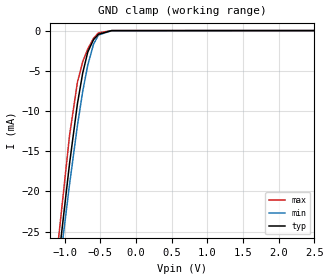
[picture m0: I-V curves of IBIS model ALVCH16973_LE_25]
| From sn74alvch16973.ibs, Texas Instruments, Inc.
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[Model]   ALVCH16973_LE_25
Model_type  Input
Vinl=0.7
Vinh=1.7
| variable   typ   min   max
C_comp   2.42pF   2.00pF   2.96pF
[Temperature Range]   40   100   -40
| Ambient temperature   25   85   -40
[Voltage range]   2.5   2.3   2.7
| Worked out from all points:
|   GND clamp passes 1 mA (typ) near -0.58 V on its own axis
[GND Clamp]
| ALVCH16973_LE_25
|   Voltage   I(typ)   I(min)   I(max)
-2.5V     -154.3mA   -145.9mA   -164.5mA
-1.145V   -33.47mA   -34.86mA   -31.33mA
-1.105V   -30.2mA    -31.85mA   -27.72mA
-1.085V   -28.58mA   -30.35mA   -25.93mA
-930mV    -16.54mA   -19.13mA   -13.04mA
-820mV    -9.124mA   -11.84mA   -6.44mA
-745mV    -5.25mA    -7.527mA   -3.847mA
-675mV    -2.681mA   -4.31mA    -2.304mA
-595mV    -1.134mA   -1.719mA   -967.5uA
-525mV    -460.2uA   -548.5uA   -284.1uA
-340mV    -6.934uA   -11.01uA   -976nA
2.5V      156.4pA    884.6pA    34.32pA
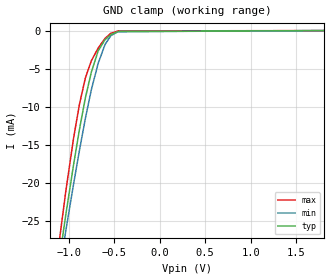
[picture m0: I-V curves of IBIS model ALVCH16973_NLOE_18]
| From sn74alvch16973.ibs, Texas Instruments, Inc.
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[Model]   ALVCH16973_NLOE_18
Model_type  Input
Vinl=0.5775
Vinh=1.2675
| variable   typ   min   max
C_comp   2.50pF   2.12pF   2.98pF
[Temperature Range]   40   100   -40
| Ambient temperature   25   85   -40
[Voltage range]   1.8   1.65   1.95
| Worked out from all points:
|   GND clamp passes 1 mA (typ) near -0.58 V on its own axis
[GND Clamp]
| ALVCH16973_NLOE_18
|   Voltage   I(typ)   I(min)   I(max)
-1.8V     -90.36mA   -87.06mA   -94.23mA
-1.34V    -49.88mA   -49.94mA   -49.51mA
-1.03V    -24.19mA   -26.29mA   -21.12mA
-945mV    -17.65mA   -20.18mA   -14.16mA
-880mV    -12.98mA   -15.72mA   -9.673mA
-815mV    -8.831mA   -11.53mA   -6.213mA
-750mV    -5.474mA   -7.789mA   -3.976mA
-675mV    -2.681mA   -4.31mA    -2.304mA
-600mV    -1.199mA   -1.844mA   -1.035mA
-535mV    -533.8uA   -655.1uA   -350.4uA
-455mV    -127.2uA   -144.7uA   -47.79uA
1.8V      127.8pA    817.9pA    24.46pA
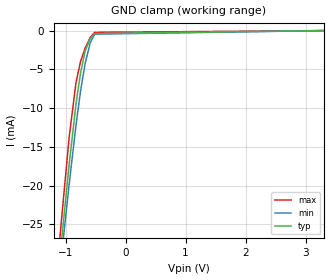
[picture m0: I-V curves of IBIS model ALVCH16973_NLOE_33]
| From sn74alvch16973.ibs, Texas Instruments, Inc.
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[Model]   ALVCH16973_NLOE_33
Model_type  Input
Vinl=0.8
Vinh=2.0
| variable   typ   min   max
C_comp   2.36pF   1.92pF   2.99pF
[Temperature Range]   40   100   -40
| Ambient temperature   25   85   -40
[Voltage range]   3.3   3   3.6
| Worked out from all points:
|   GND clamp passes 1 mA (typ) near -0.58 V on its own axis
[GND Clamp]
| ALVCH16973_NLOE_33
|   Voltage   I(typ)   I(min)   I(max)
-3.3V     -229.2mA   -214.9mA   -246.1mA
-1.15V    -33.88mA   -35.24mA   -31.79mA
-1.125V   -31.83mA   -33.35mA   -29.52mA
-1.1V     -29.79mA   -31.47mA   -27.27mA
-1.075V   -27.77mA   -29.61mA   -25.05mA
-940mV    -17.28mA   -19.83mA   -13.78mA
-825mV    -9.422mA   -12.15mA   -6.674mA
-750mV    -5.474mA   -7.789mA   -3.976mA
-675mV    -2.681mA   -4.31mA    -2.304mA
-590mV    -1.072mA   -1.6mA     -901.9uA
-515mV    -393.5uA   -457.8uA   -227.6uA
3.3V      193.8pA    964pA      46.32pA
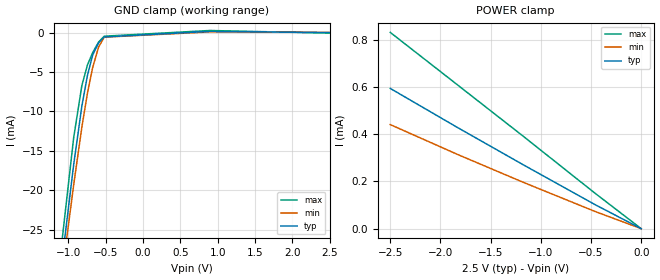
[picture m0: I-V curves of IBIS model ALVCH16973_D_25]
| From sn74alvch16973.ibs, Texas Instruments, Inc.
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[Model]   ALVCH16973_D_25
Model_type  Input
Vinl=0.7
Vinh=1.7
| variable   typ   min   max
C_comp   2.35pF   1.88pF   2.85pF
[Temperature Range]   40   100   -40
| Ambient temperature   25   85   -40
[Voltage range]   2.5   2.3   2.7
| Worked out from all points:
|   GND clamp passes 1 mA (typ) near -0.57 V on its own axis
[GND Clamp]
| ALVCH16973_D_25
|   Voltage   I(typ)   I(min)   I(max)
-2.5V     -155.1mA   -146.5mA   -165.4mA
-1.175V   -36.25mA   -37.4mA    -34.46mA
-1.13V    -32.52mA   -33.97mA   -30.34mA
-1.09V    -29.25mA   -30.96mA   -26.73mA
-930mV    -16.76mA   -19.32mA   -13.34mA
-820mV    -9.311mA   -11.99mA   -6.705mA
-745mV    -5.418mA   -7.653mA   -4.094mA
-675mV    -2.833mA   -4.418mA   -2.535mA
-595mV    -1.272mA   -1.81mA    -1.181mA
-520mV    -551.2uA   -580.9uA   -452.6uA
895mV     155.5uA    88.25uA    267.9uA
2.5V      166.5pA    30.52uA    -60.81uA
[POWER Clamp]
| ALVCH16973_D_25
|   Voltage   I(typ)   I(min)   I(max)
-2.5V     593.2uA    440.2uA    830.2uA
-1.825V   426.6uA    313.1uA    606.5uA
-1.175V   270.2uA    196uA      390.8uA
-460mV    101.7uA    72.75uA    149.9uA
-31.15fV  166.5pA    873.6pA    50.54pA
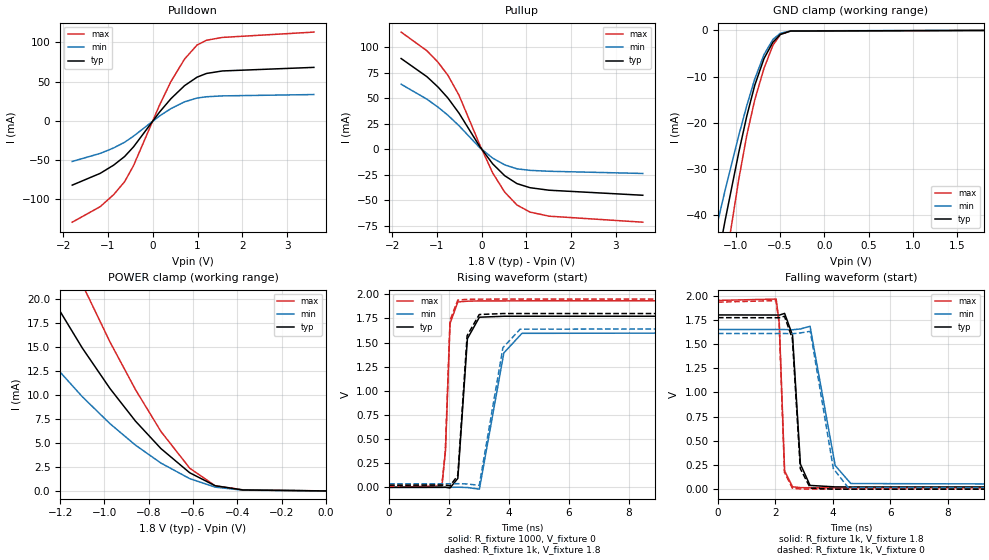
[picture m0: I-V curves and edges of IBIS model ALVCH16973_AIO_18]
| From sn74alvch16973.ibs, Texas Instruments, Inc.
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[Model]   ALVCH16973_AIO_18
Model_type  I/O
Vinl=0.5775
Vinh=1.2675
Enable   Active-Low
Vref =   0
Rref =   1000
Cref =   30p
Vmeas =   0.9
| variable   typ   min   max
C_comp   3.52pF   3.13pF   3.77pF
| C_pullup   4.75pF   3.65pF   5.30pF
| C_pulldown   5.07pF   3.29pF   6.70pF
| C_tri-state   3.52pF   3.13pF   3.77pF
[Temperature Range]   40   100   -40
| Ambient temperature   25   85   -40
[Voltage range]   1.8   1.65   1.95
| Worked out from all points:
|   slope of the pulldown table from 0 to 0.27 V, typ, clamps not added: 13.8 ohm
|   slope of the pullup table from 0 to 0.27 V, typ, clamps not added: 17.6 ohm
|   GND clamp passes 1 mA (typ) near -0.50 V on its own axis
|   POWER clamp passes 1 mA (typ) near -0.55 V on its own axis
|   rising waveform, R_fixture 1000, V_fixture 0: 20-80 % time 196ps typ, 355ps min, 120ps max; typ from 0 V to 1.77 V
|   falling waveform, R_fixture 1k, V_fixture 1.8: 20-80 % time 202ps typ, 380ps min, 121ps max; typ from 1.8 V to 0.023 V
|   rising waveform, R_fixture 1k, V_fixture 1.8: 20-80 % time 192ps typ, 335ps min, 119ps max; typ from 0.023 V to 1.8 V
|   falling waveform, R_fixture 1k, V_fixture 0: 20-80 % time 197ps typ, 366ps min, 120ps max; typ from 1.77 V to 0 V
[GND Clamp]
| ALVCH16973_AIO_18
|   Voltage   I(typ)   I(min)   I(max)
-1.8V     -114.4mA   -93.74mA   -142.9mA
-1.55V    -86.48mA   -71.1mA    -108.3mA
-1.325V   -62.23mA   -51.54mA   -77.86mA
-1.12V    -41.21mA   -34.65mA   -51.11mA
-965mV    -26.41mA   -22.72mA   -32.22mA
-875mV    -18.58mA   -16.31mA   -22.75mA
-785mV    -11.9mA    -10.53mA   -15.06mA
-680mV    -6.088mA   -5.234mA   -8.189mA
-580mV    -2.563mA   -1.963mA   -3.232mA
-495mV    -862.4uA   -609.1uA   -886.9uA
-380mV    -137.5uA   -100.9uA   -157.2uA
1.8V      633.6pA    17.14uA    -35.19uA
[POWER Clamp]
| ALVCH16973_AIO_18
|   Voltage   I(typ)   I(min)   I(max)
-1.8V     46.9mA     32mA       62.55mA
-1.505V   31.94mA    21.45mA    44.13mA
-1.37V    25.77mA    17.18mA    36.18mA
-1.235V   20.07mA    13.3mA     28.63mA
-1.1V     14.92mA    9.837mA    21.56mA
-975mV    10.69mA    7.019mA    15.55mA
-860mV    7.289mA    4.782mA    10.58mA
-745mV    4.421mA    2.907mA    6.209mA
-615mV    1.894mA    1.281mA    2.37mA
-500mV    537.7uA    395.3uA    541.3uA
-375mV    99.26uA    77.48uA    115.9uA
-16.28fV  633.6pA    1.888nA    58.65pA
[Pulldown]
| ALVCH16973_AIO_18
|   Voltage   I(typ)   I(min)   I(max)
-1.8V     -81.77mA   -51.62mA   -129mA
-1.175V   -66.78mA   -41.36mA   -109.2mA
-875mV    -56.33mA   -34.41mA   -93.93mA
-630mV    -45.37mA   -27.16mA   -77.47mA
-430mV    -33mA      -19.38mA   -56.92mA
150mV     11.21mA    6.297mA    20.03mA
405mV     28.31mA    15.69mA    50.14mA
710mV     44.96mA    24.35mA    78.83mA
990mV     55.79mA    29.2mA     96.74mA
1.2V      60.49mA    30.8mA     102.8mA
1.555V    63.68mA    31.91mA    106.4mA
3.6V      68.24mA    33.63mA    113.2mA
[Pullup]
| ALVCH16973_AIO_18
|   Voltage   I(typ)   I(min)   I(max)
-1.8V     89.09mA    63.89mA    115mA
-1.22V    71.17mA    49.14mA    96.57mA
-975mV    61.12mA    41.42mA    85.41mA
-755mV    50.4mA     33.55mA    72.69mA
-505mV    35.45mA    23.15mA    52.97mA
-50mV     3.259mA    2.011mA    5.287mA
245mV     -14.09mA   -8.478mA   -22.97mA
515mV     -25.78mA   -15.14mA   -41.86mA
790mV     -33.53mA   -19.02mA   -54.5mA
1.08V     -37.51mA   -20.51mA   -61.41mA
1.505V    -39.97mA   -21.4mA    -65.42mA
3.6V      -44.91mA   -23.56mA   -71.31mA
[Ramp]
| ALVCH16973_AIO_18
| variable   typ   min   max
dV/dt_r   1.07/2.04E-10   0.98/3.64E-10   1.17/1.23E-10
dV/dt_f   1.09/2.14E-10   0.99/3.98E-10   1.17/1.37E-10
R_load = 1000
[Rising Waveform]
| ALVCH16973_AIO_18
R_fixture =   1000
C_fixture =   0
L_fixture =   0
V_fixture =   0
V_fixture_min = 0
V_fixture_max = 0
|   Time   V(typ)   V(min)   V(max)
0s        5.832nV    32.59nV    120.7pV
1.765ns   703.9uV    -31.88uV   14.62mV
1.885ns   1.292mV    13.07uV    389.7mV
2.035ns   -5.864mV   205.1uV    1.697V
2.295ns   92.99mV    1.518mV    1.92V
2.615ns   1.54V      -1.385mV   1.928V
3.015ns   1.762V     -18.58mV   1.931V
3.83ns    1.772V     1.392V     1.931V
4.435ns   1.772V     1.595V     1.932V
29.99ns   1.772V     1.608V     1.932V
[Falling Waveform]
| ALVCH16973_AIO_18
R_fixture =   1k
C_fixture =   0
L_fixture =   0
V_fixture =   1.8
V_fixture_min = 1.65
V_fixture_max = 1.95
|   Time   V(typ)   V(min)   V(max)
0s        1.8V       1.65V      1.95V
2.025ns   1.799V     1.65V      1.964V
2.135ns   1.798V     1.65V      1.712V
2.32ns    1.816V     1.649V     187.7mV
2.595ns   1.591V     1.647V     24.59mV
2.87ns    258.7mV    1.655V     15.86mV
3.205ns   38.68mV    1.683V     14.44mV
4.08ns    23.45mV    244.1mV    13.97mV
4.625ns   23.1mV     58.06mV    13.95mV
29.99ns   23.03mV    37.16mV    13.95mV
[Rising Waveform]
| ALVCH16973_AIO_18
R_fixture =   1k
C_fixture =   0
L_fixture =   0
V_fixture =   1.8
V_fixture_min = 1.65
V_fixture_max = 1.95
|   Time   V(typ)   V(min)   V(max)
0s        23.03mV    37.16mV    13.95mV
1.765ns   23.67mV    37.15mV    29.67mV
1.875ns   24.14mV    37.19mV    360.8mV
2.035ns   17.02mV    37.38mV    1.731V
2.295ns   123.2mV    38.46mV    1.94V
2.605ns   1.571V     35.35mV    1.947V
3.01ns    1.79V      20.83mV    1.949V
3.8ns     1.8V       1.447V     1.95V
4.375ns   1.8V       1.638V     1.95V
29.99ns   1.8V       1.65V      1.95V
[Falling Waveform]
| ALVCH16973_AIO_18
R_fixture =   1k
C_fixture =   0
L_fixture =   0
V_fixture =   0
V_fixture_min = 0
V_fixture_max = 0
|   Time   V(typ)   V(min)   V(max)
0s        1.772V     1.608V     1.932V
2.02ns    1.771V     1.608V     1.948V
2.13ns    1.771V     1.608V     1.711V
2.315ns   1.786V     1.608V     174mV
2.59ns    1.554V     1.606V     10.13mV
2.865ns   212.8mV    1.614V     1.841mV
3.215ns   11.45mV    1.631V     429.7uV
4.015ns   363.3uV    213.1mV    17.39uV
4.525ns   66.69uV    18.79mV    2.435uV
29.99ns   8.339nV    27.98nV    5.646nV
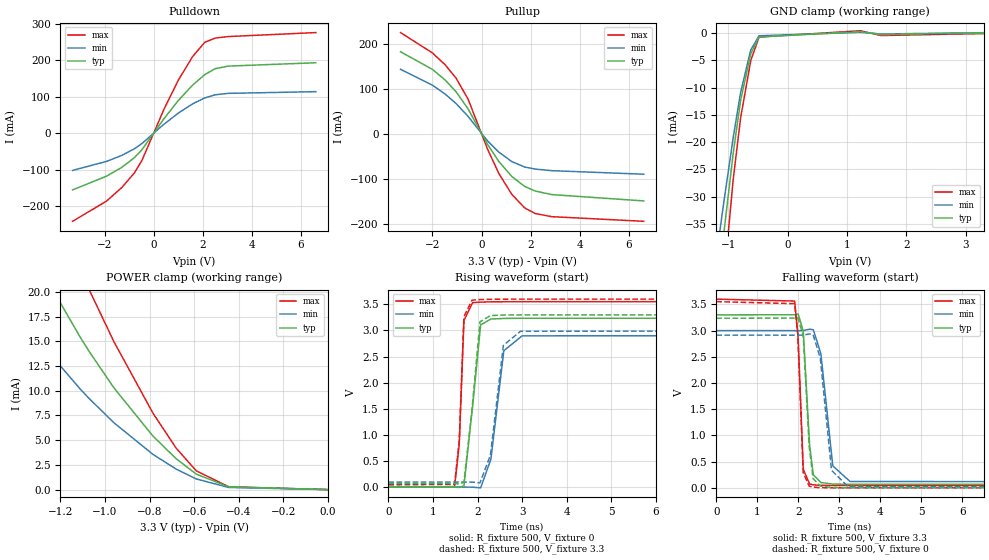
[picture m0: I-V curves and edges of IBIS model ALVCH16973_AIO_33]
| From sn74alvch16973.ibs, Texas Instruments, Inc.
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[Model]   ALVCH16973_AIO_33
Model_type  I/O
Vinl=0.8
Vinh=2.0
Enable   Active-Low
Vref =   0
Rref =   500
Cref =   50p
Vmeas =   1.5
| variable   typ   min   max
C_comp   3.35pF   2.92pF   3.62pF
| C_pullup   4.46pF   3.55pF   5.27pF
| C_pulldown   4.40pF   3.13pF   6.10pF
| C_tri-state   3.35pF   2.92pF   3.62pF
[Temperature Range]   40   100   -40
| Ambient temperature   25   85   -40
[Voltage range]   3.3   3   3.6
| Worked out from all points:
|   slope of the pulldown table from 0 to 0.495 V, typ, clamps not added: 10.7 ohm
|   slope of the pullup table from 0 to 0.495 V, typ, clamps not added: 10.9 ohm
|   GND clamp passes 1 mA (typ) near -0.50 V on its own axis
|   POWER clamp passes 1 mA (typ) near -0.55 V on its own axis
|   rising waveform, R_fixture 500, V_fixture 0: 20-80 % time 139ps typ, 219ps min, 87.2ps max; typ from 0 V to 3.23 V
|   falling waveform, R_fixture 500, V_fixture 3.3: 20-80 % time 128ps typ, 203ps min, 93.3ps max; typ from 3.3 V to 0.066 V
|   rising waveform, R_fixture 500, V_fixture 3.3: 20-80 % time 137ps typ, 214ps min, 86.6ps max; typ from 0.066 V to 3.3 V
|   falling waveform, R_fixture 500, V_fixture 0: 20-80 % time 127ps typ, 195ps min, 93.1ps max; typ from 3.23 V to 0 V
[GND Clamp]
| ALVCH16973_AIO_33
|   Voltage   I(typ)   I(min)   I(max)
-3.3V     -292.5mA   -240.9mA   -356.9mA
-1.285V   -58.1mA    -48.21mA   -72.65mA
-1.195V   -48.82mA   -40.75mA   -60.84mA
-1.165V   -45.78mA   -38.31mA   -56.96mA
-1.09V    -38.32mA   -32.32mA   -47.42mA
-915mV    -22.02mA   -19.13mA   -26.81mA
-790mV    -12.29mA   -10.87mA   -15.52mA
-620mV    -3.805mA   -3.097mA   -5.052mA
-480mV    -724.5uA   -513.5uA   -734.2uA
1.225V    241.6uA    133.1uA    415.1uA
1.57V     -286.1uA   -180.8uA   -465.2uA
3.3V      1.144nA    60.8uA     -106.7uA
[POWER Clamp]
| ALVCH16973_AIO_33
|   Voltage   I(typ)   I(min)   I(max)
-3.3V     143.6mA    105.5mA    167.4mA
-1.53V    33.24mA    22.37mA    45.78mA
-1.5V     31.81mA    21.37mA    43.97mA
-1.275V   21.8mA     14.48mA    30.94mA
-1.11V    15.37mA    10.14mA    22.17mA
-1.07V    13.94mA    9.187mA    20.17mA
-960mV    10.29mA    6.764mA    14.96mA
-785mV    5.416mA    3.563mA    7.735mA
-680mV    3.107mA    2.063mA    4.169mA
-590mV    1.562mA    1.075mA    1.89mA
-445mV    281.1uA    216.8uA    283.5uA
-48.03fV  1.144nA    2.341nA    157.4pA
[Pulldown]
| ALVCH16973_AIO_33
|   Voltage   I(typ)   I(min)   I(max)
-3.3V     -155.3mA   -102mA     -241.3mA
-1.92V    -117.9mA   -77.39mA   -186.1mA
-1.295V   -93.6mA    -60.93mA   -148.7mA
-780mV    -66.83mA   -42.71mA   -108.4mA
-475mV    -45.21mA   -28.32mA   -74.34mA
405mV     38.2mA     23.55mA    63.12mA
995mV     88.61mA    54.39mA    143.9mA
1.585V    131.4mA    80.05mA    209.4mA
2.08V     160mA      96.3mA     248.5mA
2.505V    176.4mA    104.9mA    260.1mA
3.03V     183.4mA    108.8mA    264.3mA
6.6V      192.6mA    113.5mA    275.2mA
[Pullup]
| ALVCH16973_AIO_33
|   Voltage   I(typ)   I(min)   I(max)
-3.3V     183mA      143.8mA    225.7mA
-2V       143.6mA    108.5mA    180.3mA
-1.48V    119.8mA    88.48mA    153.7mA
-1.04V    93.93mA    67.7mA     124.3mA
-550mV    55.76mA    39.02mA    77.44mA
245mV     -23.6mA    -15.83mA   -34.29mA
705mV     -61.65mA   -40.84mA   -88.44mA
1.23V     -94.91mA   -61.64mA   -134.7mA
1.755V    -117.1mA   -73.97mA   -165mA
2.185V    -127.4mA   -78.46mA   -177.5mA
2.86V     -135.3mA   -82.02mA   -184.5mA
6.6V      -149.4mA   -89.88mA   -194.8mA
[Ramp]
| ALVCH16973_AIO_33
| variable   typ   min   max
dV/dt_r   1.95/1.43E-10   1.76/2.21E-10   2.13/9.04E-11
dV/dt_f   1.95/1.35E-10   1.76/2.15E-10   2.13/9.92E-11
R_load = 500
[Rising Waveform]
| ALVCH16973_AIO_33
R_fixture =   500
C_fixture =   0
L_fixture =   0
V_fixture =   0
V_fixture_min = 0
V_fixture_max = 0
|   Time   V(typ)   V(min)   V(max)
0s        8.745nV    32.05nV    337.5pV
1.485ns   856.9uV    105.7uV    8.51mV
1.59ns    -5.513mV   317.9uV    819mV
1.695ns   25.09mV    819.4uV    3.189V
1.89ns    1.551V     -1.428mV   3.532V
2.07ns    3.106V     -14.22mV   3.543V
2.3ns     3.219V     535.5mV    3.548V
2.59ns    3.23V      2.611V     3.55V
3ns       3.234V     2.897V     3.551V
29.99ns   3.235V     2.913V     3.552V
[Falling Waveform]
| ALVCH16973_AIO_33
R_fixture =   500
C_fixture =   0
L_fixture =   0
V_fixture =   3.3
V_fixture_min = 3
V_fixture_max = 3.6
|   Time   V(typ)   V(min)   V(max)
0s        3.3V       3V         3.6V
1.91ns    3.302V     2.999V     3.563V
1.995ns   3.319V     2.998V     2.871V
2.12ns    2.991V     3V         354.3mV
2.275ns   815.6mV    3.027V     74.1mV
2.365ns   248.2mV    3.017V     57.63mV
2.55ns    102.1mV    2.558V     48.09mV
2.84ns    71.94mV    419mV      44.92mV
3.26ns    67.3mV     122mV      43.94mV
29.99ns   66.45mV    96.86mV    43.74mV
[Rising Waveform]
| ALVCH16973_AIO_33
R_fixture =   500
C_fixture =   0
L_fixture =   0
V_fixture =   3.3
V_fixture_min = 3
V_fixture_max = 3.6
|   Time   V(typ)   V(min)   V(max)
0s        66.45mV    96.86mV    43.74mV
1.485ns   67.2mV     96.96mV    52.81mV
1.59ns    60.91mV    97.14mV    891.7mV
1.695ns   93.03mV    97.57mV    3.265V
1.875ns   1.475V     96.04mV    3.58V
2.055ns   3.165V     81.7mV     3.592V
2.29ns    3.285V     613.2mV    3.597V
2.58ns    3.295V     2.715V     3.599V
2.965ns   3.299V     2.985V     3.6V
29.99ns   3.3V       3V         3.6V
[Falling Waveform]
| ALVCH16973_AIO_33
R_fixture =   500
C_fixture =   0
L_fixture =   0
V_fixture =   0
V_fixture_min = 0
V_fixture_max = 0
|   Time   V(typ)   V(min)   V(max)
0s        3.235V     2.913V     3.552V
1.91ns    3.238V     2.912V     3.513V
1.985ns   3.25V      2.912V     2.937V
2.12ns    2.899V     2.914V     288.9mV
2.265ns   788.3mV    2.936V     31.98mV
2.36ns    175.7mV    2.923V     13.56mV
2.535ns   34.51mV    2.474V     4.419mV
2.81ns    5.609mV    333.6mV    1.267mV
3.215ns   868.5uV    22.71mV    222.3uV
29.99ns   29.46nV    114.4nV    -3.055nV
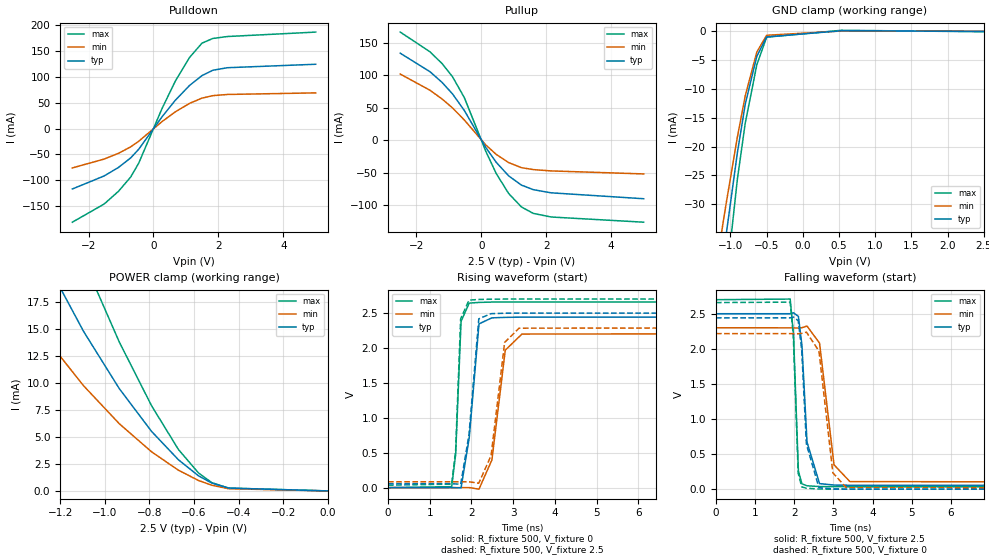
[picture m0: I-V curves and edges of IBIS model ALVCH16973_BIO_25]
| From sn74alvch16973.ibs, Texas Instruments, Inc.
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[Model]   ALVCH16973_BIO_25
Model_type  I/O
Vinl=0.7
Vinh=1.7
Enable   Active-Low
Vref =   0
Rref =   500
Cref =   30p
Vmeas =   1.25
| variable   typ   min   max
C_comp   3.17pF   2.84pF   3.43pF
| C_pullup   4.36pF   3.39pF   5.01pF
| C_pulldown   4.44pF   3.03pF   6.17pF
| C_tri-state   3.17pF   2.84pF   3.43pF
[Temperature Range]   40   100   -40
| Ambient temperature   25   85   -40
[Voltage range]   2.5   2.3   2.7
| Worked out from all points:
|   slope of the pulldown table from 0 to 0.375 V, typ, clamps not added: 11.7 ohm
|   slope of the pullup table from 0 to 0.375 V, typ, clamps not added: 13.2 ohm
|   GND clamp passes 1 mA (typ) near -0.50 V on its own axis
|   POWER clamp passes 1 mA (typ) near -0.55 V on its own axis
|   rising waveform, R_fixture 500, V_fixture 0: 20-80 % time 149ps typ, 240ps min, 96.4ps max; typ from 0 V to 2.44 V
|   falling waveform, R_fixture 500, V_fixture 2.5: 20-80 % time 142ps typ, 246ps min, 88.2ps max; typ from 2.5 V to 0.055 V
|   rising waveform, R_fixture 500, V_fixture 2.5: 20-80 % time 144ps typ, 230ps min, 90.5ps max; typ from 0.055 V to 2.5 V
|   falling waveform, R_fixture 500, V_fixture 0: 20-80 % time 136ps typ, 234ps min, 88.6ps max; typ from 2.44 V to 0 V
[GND Clamp]
| ALVCH16973_BIO_25
|   Voltage   I(typ)   I(min)   I(max)
-2.5V     -196mA     -160.6mA   -242mA
-1.295V   -59.12mA   -49.03mA   -73.93mA
-1.26V    -55.47mA   -46.1mA    -69.3mA
-1.19V    -48.28mA   -40.32mA   -60.15mA
-1.1V     -39.27mA   -33.09mA   -48.64mA
-1.06V    -35.37mA   -29.95mA   -43.64mA
-905mV    -21.13mA   -18.41mA   -25.74mA
-795mV    -12.6mA    -11.15mA   -15.87mA
-635mV    -4.298mA   -3.567mA   -5.766mA
-500mV    -955.7uA   -674.7uA   -1.004mA
535mV     116.6uA    68.81uA    193.2uA
2.5V      837.7pA    30.92uA    -60.81uA
[POWER Clamp]
| ALVCH16973_BIO_25
|   Voltage   I(typ)   I(min)   I(max)
-2.5V     88.63mA    62.79mA    110mA
-1.52V    32.72mA    21.99mA    45.11mA
-1.495V   31.53mA    21.17mA    43.61mA
-1.27V    21.55mA    14.31mA    30.61mA
-1.095V   14.79mA    9.751mA    21.37mA
-935mV    9.486mA    6.232mA    13.81mA
-790mV    5.511mA    3.621mA    7.886mA
-670mV    2.89mA     1.921mA    3.844mA
-580mV    1.401mA    968.8uA    1.666mA
-520mV    722.5uA    523.2uA    765.4uA
-445mV    264.7uA    204.2uA    262.3uA
-31.15fV  837.7pA    2.097nA    92.36pA
[Pulldown]
| ALVCH16973_BIO_25
|   Voltage   I(typ)   I(min)   I(max)
-2.5V     -116.7mA   -75.94mA   -180.9mA
-1.52V    -91.51mA   -58.89mA   -145.8mA
-1.075V   -74.92mA   -47.63mA   -121mA
-700mV    -56.45mA   -35.17mA   -93.45mA
-455mV    -39.93mA   -24.42mA   -66.85mA
265mV     22.95mA    13.69mA    39.02mA
675mV     54.98mA    32.57mA    92.13mA
1.115V    83.7mA     48.99mA    137.9mA
1.495V    102.6mA    59.02mA    165.3mA
1.83V     112.9mA    63.78mA    174.4mA
2.275V    117.8mA    66.07mA    178.1mA
5V        124.5mA    69.16mA    186.7mA
[Pullup]
| ALVCH16973_BIO_25
|   Voltage   I(typ)   I(min)   I(max)
-2.5V     134mA      101.9mA    166.5mA
-1.585V   105.6mA    77.05mA    136.2mA
-1.21V    89.01mA    63.51mA    118mA
-890mV    71.4mA     49.86mA    97.84mA
-525mV    45.85mA    31.23mA    65.64mA
135mV     -10.99mA   -7.123mA   -16.78mA
455mV     -33.71mA   -21.58mA   -50.91mA
840mV     -54.72mA   -34.35mA   -81.84mA
1.235V    -68.97mA   -42.11mA   -102.6mA
1.6V      -75.94mA   -45.08mA   -112.5mA
2.145V    -80.8mA    -47.11mA   -118mA
5V        -89.91mA   -51.75mA   -126mA
[Ramp]
| ALVCH16973_BIO_25
| variable   typ   min   max
dV/dt_r   1.48/1.54E-10   1.35/2.48E-10   1.60/9.77E-11
dV/dt_f   1.49/1.55E-10   1.35/2.60E-10   1.62/9.20E-11
R_load = 500
[Rising Waveform]
| ALVCH16973_BIO_25
R_fixture =   500
C_fixture =   0
L_fixture =   0
V_fixture =   0
V_fixture_min = 0
V_fixture_max = 0
|   Time   V(typ)   V(min)   V(max)
0s        6.767nV    30.52nV    187.6pV
1.525ns   1.229mV    23.3uV     14.23mV
1.62ns    -1.17mV    222.4uV    472.5mV
1.75ns    -2.977mV   1.088mV    2.381V
1.945ns   709mV      870.4uV    2.642V
2.18ns    2.345V     -21.84mV   2.652V
2.49ns    2.431V     397.7mV    2.657V
2.81ns    2.438V     1.968V     2.658V
3.21ns    2.441V     2.199V     2.658V
29.99ns   2.441V     2.217V     2.659V
[Falling Waveform]
| ALVCH16973_BIO_25
R_fixture =   500
C_fixture =   0
L_fixture =   0
V_fixture =   2.5
V_fixture_min = 2.3
V_fixture_max = 2.7
|   Time   V(typ)   V(min)   V(max)
0s        2.5V       2.3V       2.7V
1.895ns   2.5V       2.299V     2.709V
1.98ns    2.514V     2.298V     2.204V
2.105ns   2.462V     2.296V     258.3mV
2.195ns   2.055V     2.301V     76.5mV
2.325ns   671.3mV    2.324V     47.82mV
2.645ns   79.29mV    2.082V     37.29mV
3.015ns   58.55mV    347.3mV    35.29mV
3.42ns    55.4mV     108.1mV    34.87mV
29.99ns   54.78mV    83.35mV    34.78mV
[Rising Waveform]
| ALVCH16973_BIO_25
R_fixture =   500
C_fixture =   0
L_fixture =   0
V_fixture =   2.5
V_fixture_min = 2.3
V_fixture_max = 2.7
|   Time   V(typ)   V(min)   V(max)
0s        54.78mV    83.35mV    34.78mV
1.525ns   55.86mV    83.39mV    50.26mV
1.62ns    53.35mV    83.57mV    532.2mV
1.74ns    47.29mV    84.19mV    2.416V
1.94ns    758.2mV    83.71mV    2.685V
2.175ns   2.417V     62.93mV    2.694V
2.47ns    2.491V     459.8mV    2.698V
2.795ns   2.497V     2.079V     2.7V
3.14ns    2.499V     2.283V     2.7V
29.99ns   2.5V       2.3V       2.7V
[Falling Waveform]
| ALVCH16973_BIO_25
R_fixture =   500
C_fixture =   0
L_fixture =   0
V_fixture =   0
V_fixture_min = 0
V_fixture_max = 0
|   Time   V(typ)   V(min)   V(max)
0s        2.441V     2.217V     2.659V
1.895ns   2.442V     2.217V     2.665V
1.975ns   2.454V     2.216V     2.185V
2.1ns     2.401V     2.215V     227.9mV
2.19ns    1.983V     2.22V      33.05mV
2.31ns    639.5mV    2.238V     13.33mV
2.63ns    21.63mV    1.969V     2.506mV
2.985ns   3.453mV    234.6mV    537.1uV
3.325ns   701.5uV    21.74mV    130.8uV
29.99ns   29.78nV    71.21nV    670.3pV
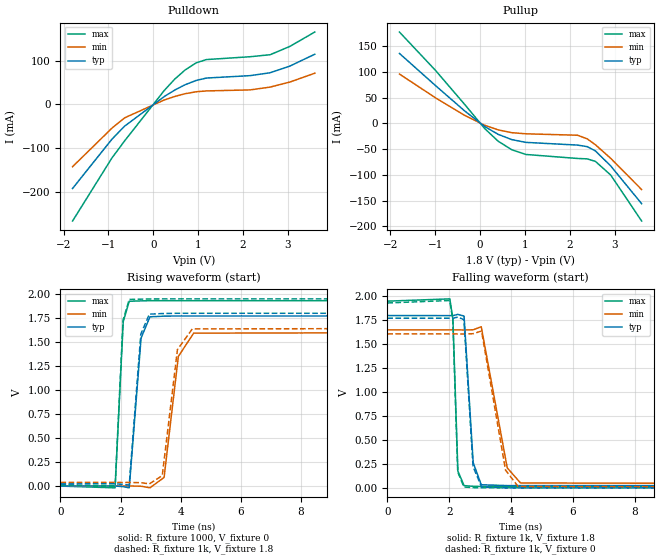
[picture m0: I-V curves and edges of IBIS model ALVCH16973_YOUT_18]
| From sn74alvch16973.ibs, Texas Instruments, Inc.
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[Model]   ALVCH16973_YOUT_18
Model_type  Output
Vref =   0
Rref =   1000
Cref =   30p
Vmeas =   0.9
| variable   typ   min   max
C_comp   4.28pF   2.94pF   5.47pF
| C_pullup   4.27pF   3.18pF   4.69pF
| C_pulldown   4.28pF   2.94pF   5.47pF
[Temperature Range]   40   100   -40
| Ambient temperature   25   85   -40
[Voltage range]   1.8   1.65   1.95
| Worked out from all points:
|   slope of the pulldown table from 0 to 0.27 V, typ, clamps not added: 13.8 ohm
|   slope of the pullup table from 0 to 0.27 V, typ, clamps not added: 17.6 ohm
|   rising waveform, R_fixture 1000, V_fixture 0: 20-80 % time 180ps typ, 328ps min, 120ps max; typ from 0 V to 1.77 V
|   falling waveform, R_fixture 1k, V_fixture 1.8: 20-80 % time 153ps typ, 287ps min, 102ps max; typ from 1.8 V to 0.023 V
|   rising waveform, R_fixture 1k, V_fixture 1.8: 20-80 % time 175ps typ, 319ps min, 119ps max; typ from 0.023 V to 1.8 V
|   falling waveform, R_fixture 1k, V_fixture 0: 20-80 % time 154ps typ, 282ps min, 102ps max; typ from 1.77 V to 0 V
[Pulldown]
| ALVCH16973_YOUT_18
|   Voltage   I(typ)   I(min)   I(max)
-1.8V     -192.8mA   -142.9mA   -267.4mA
-920mV    -79.63mA   -54.42mA   -122.6mA
-640mV    -50.05mA   -31.02mA   -83.84mA
245mV     17.89mA    10mA       31.85mA
480mV     32.81mA    18.1mA     57.97mA
705mV     44.72mA    24.23mA    78.43mA
955mV     54.7mA     28.78mA    95.07mA
1.185V    60.25mA    30.73mA    102.6mA
2.16V     65.77mA    33.09mA    109.1mA
2.605V    72.36mA    39.53mA    113.7mA
3.04V     87.44mA    50.93mA    132.5mA
3.6V      114.8mA    71.31mA    165.7mA
[Pullup]
| ALVCH16973_YOUT_18
|   Voltage   I(typ)   I(min)   I(max)
-1.8V     135.6mA    95.64mA    177.1mA
-990mV    72.77mA    49.13mA    102.1mA
-350mV    24.36mA    15.69mA    37.15mA
100mV     -6.147mA   -3.737mA   -10.06mA
400mV     -21.3mA    -12.65mA   -34.62mA
705mV     -31.58mA   -18.13mA   -51.27mA
1.02V     -36.96mA   -20.33mA   -60.42mA
2.17V     -42.21mA   -23.1mA    -68.16mA
2.385V    -45.18mA   -30.01mA   -68.92mA
2.57V     -53.53mA   -41.58mA   -73.84mA
2.91V     -82.66mA   -67.86mA   -100.3mA
3.6V      -155.9mA   -128.5mA   -189.5mA
[Ramp]
| ALVCH16973_YOUT_18
| variable   typ   min   max
dV/dt_r   1.08/1.92E-10   0.98/3.40E-10   1.17/1.29E-10
dV/dt_f   1.09/1.67E-10   1.00/3.07E-10   1.18/1.13E-10
R_load = 1000
[Rising Waveform]
| ALVCH16973_YOUT_18
R_fixture =   1000
C_fixture =   0
L_fixture =   0
V_fixture =   0
V_fixture_min = 0
V_fixture_max = 0
|   Time   V(typ)   V(min)   V(max)
0s        5.56nV     31.27nV    105.5pV
1.82ns    731.9uV    -10.7uV    -18.64mV
2.09ns    -6.282mV   234.5uV    1.712V
2.29ns    -18.63mV   946.7uV    1.925V
2.685ns   1.543V     -1.754mV   1.929V
2.98ns    1.763V     -18.06mV   1.931V
3.45ns    1.77V      89.66mV    1.931V
3.925ns   1.772V     1.35V      1.931V
4.435ns   1.772V     1.593V     1.931V
29.99ns   1.772V     1.608V     1.931V
[Falling Waveform]
| ALVCH16973_YOUT_18
R_fixture =   1k
C_fixture =   0
L_fixture =   0
V_fixture =   1.8
V_fixture_min = 1.65
V_fixture_max = 1.95
|   Time   V(typ)   V(min)   V(max)
0s        1.8V       1.65V      1.95V
2.02ns    1.799V     1.65V      1.974V
2.12ns    1.799V     1.65V      1.759V
2.28ns    1.812V     1.65V      174.9mV
2.48ns    1.794V     1.649V     23.3mV
2.775ns   263.4mV    1.651V     16.23mV
3.035ns   32.46mV    1.683V     14.72mV
3.875ns   23.43mV    208.4mV    14.01mV
4.305ns   23.15mV    50.77mV    13.99mV
29.99ns   23.08mV    37.26mV    13.98mV
[Rising Waveform]
| ALVCH16973_YOUT_18
R_fixture =   1k
C_fixture =   0
L_fixture =   0
V_fixture =   1.8
V_fixture_min = 1.65
V_fixture_max = 1.95
|   Time   V(typ)   V(min)   V(max)
0s        23.08mV    37.26mV    13.98mV
1.82ns    23.75mV    37.26mV    -2.339mV
2.085ns   17.4mV     37.47mV    1.729V
2.29ns    10.03mV    38.07mV    1.944V
2.675ns   1.583V     35.34mV    1.947V
2.96ns    1.791V     22.68mV    1.949V
3.39ns    1.797V     109.1mV    1.95V
3.895ns   1.8V       1.421V     1.95V
4.39ns    1.8V       1.637V     1.95V
29.99ns   1.8V       1.65V      1.95V
[Falling Waveform]
| ALVCH16973_YOUT_18
R_fixture =   1k
C_fixture =   0
L_fixture =   0
V_fixture =   0
V_fixture_min = 0
V_fixture_max = 0
|   Time   V(typ)   V(min)   V(max)
0s        1.772V     1.608V     1.931V
2.015ns   1.772V     1.608V     1.957V
2.115ns   1.771V     1.608V     1.761V
2.275ns   1.783V     1.608V     166.2mV
2.475ns   1.758V     1.607V     9.144mV
2.77ns    223mV      1.61V      2.201mV
3.045ns   8.657mV    1.638V     677.1uV
3.82ns    398.6uV    185.5mV    27.49uV
4.225ns   82.93uV    13.87mV    5.299uV
29.99ns   -399pV     18.55nV    -1.888nV
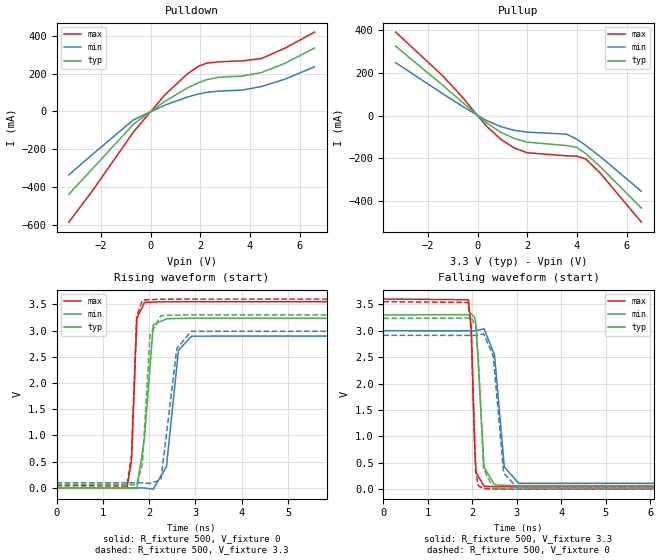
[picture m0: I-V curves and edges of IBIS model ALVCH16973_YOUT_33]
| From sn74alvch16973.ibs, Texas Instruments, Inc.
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[Model]   ALVCH16973_YOUT_33
Model_type  Output
Vref =   0
Rref =   500
Cref =   50p
Vmeas =   1.5
| variable   typ   min   max
C_comp   3.79pF   2.77pF   4.84pF
| C_pullup   3.96pF   3.12pF   4.58pF
| C_pulldown   3.63pF   2.77pF   4.84pF
[Temperature Range]   40   100   -40
| Ambient temperature   25   85   -40
[Voltage range]   3.3   3   3.6
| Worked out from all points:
|   slope of the pulldown table from 0 to 0.495 V, typ, clamps not added: 10.7 ohm
|   slope of the pullup table from 0 to 0.495 V, typ, clamps not added: 10.9 ohm
|   rising waveform, R_fixture 500, V_fixture 0: 20-80 % time 128ps typ, 169ps min, 78.2ps max; typ from 0 V to 3.23 V
|   falling waveform, R_fixture 500, V_fixture 3.3: 20-80 % time 99.7ps typ, 156ps min, 72.4ps max; typ from 3.3 V to 0.067 V
|   rising waveform, R_fixture 500, V_fixture 3.3: 20-80 % time 110ps typ, 169ps min, 77.3ps max; typ from 0.067 V to 3.3 V
|   falling waveform, R_fixture 500, V_fixture 0: 20-80 % time 100ps typ, 153ps min, 70ps max; typ from 3.23 V to 0 V
[Pulldown]
| ALVCH16973_YOUT_33
|   Voltage   I(typ)   I(min)   I(max)
-3.3V     -439.1mA   -336.5mA   -587.3mA
-2.33V    -301.5mA   -226.3mA   -417.2mA
-695mV    -67.93mA   -44.72mA   -108.9mA
590mV     54.72mA    33.7mA     89.95mA
1.48V     124.5mA    75.93mA    199mA
1.935V    152.4mA    92.13mA    239.4mA
2.265V    168.4mA    100.8mA    255.7mA
2.745V    180.7mA    107.2mA    262.5mA
3.67V     186.6mA    112.3mA    267mA
4.455V    205.4mA    131.3mA    279.7mA
5.4V      254mA      170.1mA    334.2mA
6.6V      335.3mA    236mA      419.8mA
[Pullup]
| ALVCH16973_YOUT_33
|   Voltage   I(typ)   I(min)   I(max)
-3.3V     325.7mA    248.7mA    391.9mA
-1.42V    144.4mA    104.4mA    188.9mA
-685mV    70.59mA    49.66mA    96.68mA
320mV     -30.36mA   -20.34mA   -44.02mA
935mV     -77.57mA   -50.99mA   -110.7mA
1.475V    -106.7mA   -68.45mA   -150.8mA
2V        -123.7mA   -76.96mA   -173.5mA
3.585V    -140mA     -86.41mA   -187.8mA
3.98V     -147.6mA   -108.6mA   -189.1mA
4.355V    -177mA     -139mA     -202.3mA
4.945V    -239.3mA   -191.9mA   -269.3mA
6.6V      -433.2mA   -354.3mA   -498.9mA
[Ramp]
| ALVCH16973_YOUT_33
| variable   typ   min   max
dV/dt_r   1.96/1.41E-10   1.76/1.73E-10   2.14/8.17E-11
dV/dt_f   1.96/1.03E-10   1.77/1.61E-10   2.13/7.90E-11
R_load = 500
[Rising Waveform]
| ALVCH16973_YOUT_33
R_fixture =   500
C_fixture =   0
L_fixture =   0
V_fixture =   0
V_fixture_min = 0
V_fixture_max = 0
|   Time   V(typ)   V(min)   V(max)
0s        8.387nV    30.92nV    308.4pV
1.52ns    820.3uV    102.4uV    -9.193mV
1.62ns    -5.31mV    265.2uV    530.5mV
1.735ns   -7.238mV   747.2uV    3.232V
1.9ns     952.3mV    -754.1uV   3.536V
2.09ns    3.111V     -23.38mV   3.543V
2.375ns   3.224V     408mV      3.549V
2.635ns   3.231V     2.628V     3.55V
2.92ns    3.234V     2.893V     3.551V
29.99ns   3.235V     2.913V     3.551V
[Falling Waveform]
| ALVCH16973_YOUT_33
R_fixture =   500
C_fixture =   0
L_fixture =   0
V_fixture =   3.3
V_fixture_min = 3
V_fixture_max = 3.6
|   Time   V(typ)   V(min)   V(max)
0s        3.3V       3V         3.6V
1.91ns    3.305V     2.999V     3.588V
1.975ns   3.323V     2.999V     3.064V
2.05ns    3.256V     2.999V     886.6mV
2.085ns   3.109V     3.001V     317.6mV
2.265ns   414.7mV    3.037V     56.52mV
2.5ns     83.51mV    2.544V     47.66mV
2.72ns    72.23mV    422.2mV    45.5mV
3.04ns    67.99mV    113.9mV    44.27mV
29.99ns   66.65mV    97.15mV    43.86mV
[Rising Waveform]
| ALVCH16973_YOUT_33
R_fixture =   500
C_fixture =   0
L_fixture =   0
V_fixture =   3.3
V_fixture_min = 3
V_fixture_max = 3.6
|   Time   V(typ)   V(min)   V(max)
0s        66.65mV    97.15mV    43.86mV
1.52ns    67.4mV     97.24mV    35.92mV
1.62ns    61.51mV    97.38mV    605.4mV
1.73ns    57.11mV    97.76mV    3.264V
1.855ns   458.4mV    97.76mV    3.581V
2.02ns    2.914V     85.94mV    3.59V
2.255ns   3.285V     154.9mV    3.596V
2.6ns     3.295V     2.66V      3.599V
2.91ns    3.299V     2.985V     3.6V
29.99ns   3.3V       3V         3.6V
[Falling Waveform]
| ALVCH16973_YOUT_33
R_fixture =   500
C_fixture =   0
L_fixture =   0
V_fixture =   0
V_fixture_min = 0
V_fixture_max = 0
|   Time   V(typ)   V(min)   V(max)
0s        3.235V     2.913V     3.551V
1.91ns    3.24V      2.912V     3.536V
1.975ns   3.255V     2.912V     3.001V
2.075ns   3.087V     2.913V     342.7mV
2.135ns   2.506V     2.917V     63.52mV
2.255ns   381mV      2.942V     12.86mV
2.47ns    19.69mV    2.531V     3.817mV
2.705ns   5.534mV    306.7mV    1.674mV
3.02ns    1.341mV    15.99mV    428.5uV
29.99ns   1.291nV    26.15nV    -2.649nV
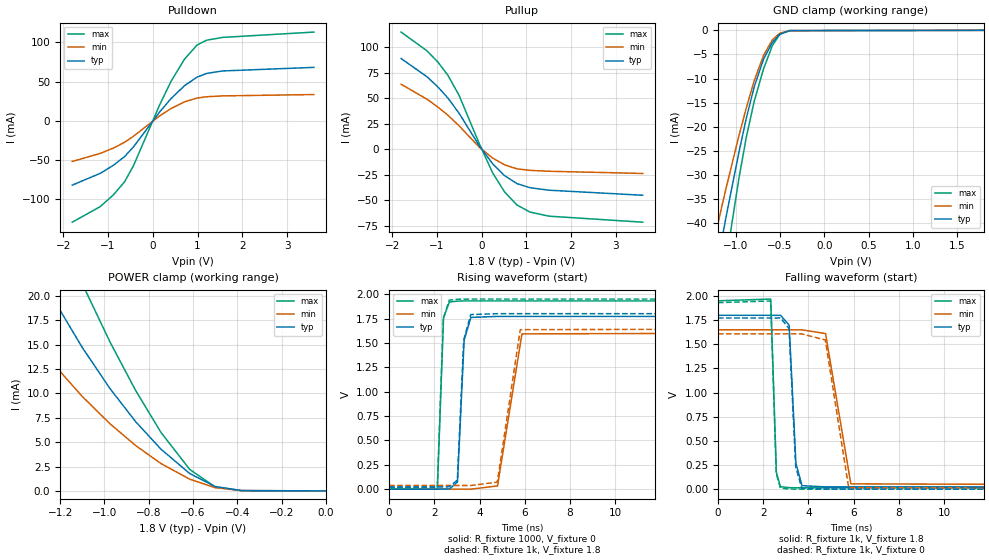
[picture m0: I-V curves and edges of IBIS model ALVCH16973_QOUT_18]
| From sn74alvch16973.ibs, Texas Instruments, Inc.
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[Model]   ALVCH16973_QOUT_18
Model_type  3-state
Enable   Active-Low
Vref =   0
Rref =   1000
Cref =   30p
Vmeas =   0.9
| variable   typ   min   max
C_comp   2.97pF   2.75pF   3.20pF
| C_pullup   4.19pF   3.20pF   4.63pF
| C_pulldown   4.52pF   2.93pF   6.10pF
| C_tri-state   2.97pF   2.75pF   3.20pF
[Temperature Range]   40   100   -40
| Ambient temperature   25   85   -40
[Voltage range]   1.8   1.65   1.95
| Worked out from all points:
|   slope of the pulldown table from 0 to 0.27 V, typ, clamps not added: 13.8 ohm
|   slope of the pullup table from 0 to 0.27 V, typ, clamps not added: 17.6 ohm
|   GND clamp passes 1 mA (typ) near -0.51 V on its own axis
|   POWER clamp passes 1 mA (typ) near -0.56 V on its own axis
|   rising waveform, R_fixture 1000, V_fixture 0: 20-80 % time 173ps typ, 313ps min, 102ps max; typ from 0 V to 1.77 V
|   falling waveform, R_fixture 1k, V_fixture 1.8: 20-80 % time 195ps typ, 348ps min, 98.7ps max; typ from 1.8 V to 0.023 V
|   rising waveform, R_fixture 1k, V_fixture 1.8: 20-80 % time 168ps typ, 296ps min, 101ps max; typ from 0.023 V to 1.8 V
|   falling waveform, R_fixture 1k, V_fixture 0: 20-80 % time 190ps typ, 335ps min, 98.3ps max; typ from 1.77 V to 0 V
[GND Clamp]
| ALVCH16973_QOUT_18
|   Voltage   I(typ)   I(min)   I(max)
-1.8V     -110.8mA   -91.09mA   -138.2mA
-1.55V    -83.72mA   -69.07mA   -104.7mA
-1.325V   -60.19mA   -50.05mA   -75.12mA
-1.115V   -39.3mA    -33.21mA   -48.56mA
-965mV    -25.41mA   -21.99mA   -30.86mA
-880mV    -18.21mA   -16.07mA   -22.15mA
-790mV    -11.67mA   -10.41mA   -14.65mA
-685mV    -5.965mA   -5.189mA   -7.969mA
-585mV    -2.492mA   -1.948mA   -3.127mA
-500mV    -802.9uA   -577.6uA   -777.6uA
-390mV    -76.91uA   -67.23uA   -41.9uA
1.8V      589.2pA    96.42nA    29.56pA
[POWER Clamp]
| ALVCH16973_QOUT_18
|   Voltage   I(typ)   I(min)   I(max)
-1.8V     46.55mA    31.75mA    62.04mA
-1.505V   31.65mA    21.24mA    43.71mA
-1.37V    25.5mA     16.99mA    35.8mA
-1.235V   19.84mA    13.14mA    28.28mA
-1.1V     14.71mA    9.689mA    21.25mA
-975mV    10.5mA     6.89mA     15.28mA
-860mV    7.13mA     4.669mA    10.34mA
-745mV    4.285mA    2.81mA     6.006mA
-615mV    1.783mA    1.203mA    2.204mA
-500mV    449uA      333.1uA    407.7uA
-380mV    38.63uA    35.82uA    19.88uA
-16.28fV  589.2pA    1.803nA    35.96pA
[Pulldown]
| ALVCH16973_QOUT_18
|   Voltage   I(typ)   I(min)   I(max)
-1.8V     -81.77mA   -51.62mA   -129mA
-1.175V   -66.78mA   -41.36mA   -109.2mA
-875mV    -56.33mA   -34.41mA   -93.93mA
-630mV    -45.37mA   -27.16mA   -77.47mA
-430mV    -33mA      -19.38mA   -56.92mA
150mV     11.21mA    6.297mA    20.03mA
405mV     28.31mA    15.69mA    50.14mA
710mV     44.96mA    24.35mA    78.83mA
990mV     55.79mA    29.2mA     96.74mA
1.2V      60.49mA    30.8mA     102.8mA
1.555V    63.68mA    31.91mA    106.4mA
3.6V      68.24mA    33.63mA    113.2mA
[Pullup]
| ALVCH16973_QOUT_18
|   Voltage   I(typ)   I(min)   I(max)
-1.8V     89.09mA    63.89mA    115mA
-1.22V    71.17mA    49.14mA    96.57mA
-975mV    61.12mA    41.42mA    85.41mA
-755mV    50.4mA     33.55mA    72.69mA
-505mV    35.45mA    23.15mA    52.97mA
-50mV     3.259mA    2.011mA    5.287mA
245mV     -14.09mA   -8.478mA   -22.97mA
515mV     -25.78mA   -15.14mA   -41.86mA
790mV     -33.53mA   -19.02mA   -54.5mA
1.08V     -37.51mA   -20.51mA   -61.41mA
1.505V    -39.97mA   -21.4mA    -65.42mA
3.6V      -44.91mA   -23.56mA   -71.31mA
[Ramp]
| ALVCH16973_QOUT_18
| variable   typ   min   max
dV/dt_r   1.07/1.82E-10   0.98/3.30E-10   1.17/1.08E-10
dV/dt_f   1.08/2.10E-10   0.99/3.63E-10   1.18/1.05E-10
R_load = 1000
[Rising Waveform]
| ALVCH16973_QOUT_18
R_fixture =   1000
C_fixture =   0
L_fixture =   0
V_fixture =   0
V_fixture_min = 0
V_fixture_max = 0
|   Time   V(typ)   V(min)   V(max)
0s        5.56nV     31.27nV    105.5pV
2.135ns   -21.25uV   3.788uV    3.23mV
2.41ns    225.4uV    -9.787uV   1.764V
2.67ns    1.275mV    -32.74uV   1.92V
3.025ns   73.66mV    401.9nV    1.929V
3.32ns    1.531V     53.99uV    1.931V
3.62ns    1.762V     216.8uV    1.931V
4.795ns   1.772V     32.86mV    1.931V
5.875ns   1.772V     1.593V     1.931V
29.99ns   1.772V     1.608V     1.931V
[Falling Waveform]
| ALVCH16973_QOUT_18
R_fixture =   1k
C_fixture =   0
L_fixture =   0
V_fixture =   1.8
V_fixture_min = 1.65
V_fixture_max = 1.95
|   Time   V(typ)   V(min)   V(max)
0s        1.8V       1.65V      1.95V
2.335ns   1.8V       1.65V      1.968V
2.585ns   1.799V     1.65V      172.7mV
2.765ns   1.801V     1.65V      25.69mV
3.15ns    1.698V     1.65V      15.62mV
3.45ns    266.3mV    1.649V     14.5mV
3.72ns    36.2mV     1.649V     14.16mV
4.76ns    23.39mV    1.611V     13.99mV
5.88ns    23.09mV    54.94mV    13.98mV
29.99ns   23.08mV    37.26mV    13.98mV
[Rising Waveform]
| ALVCH16973_QOUT_18
R_fixture =   1k
C_fixture =   0
L_fixture =   0
V_fixture =   1.8
V_fixture_min = 1.65
V_fixture_max = 1.95
|   Time   V(typ)   V(min)   V(max)
0s        23.08mV    37.26mV    13.98mV
2.135ns   23.07mV    37.26mV    17.9mV
2.395ns   23.27mV    37.25mV    1.742V
2.66ns    24.29mV    37.23mV    1.939V
3.02ns    93.5mV     37.27mV    1.948V
3.3ns     1.53V      37.32mV    1.949V
3.61ns    1.791V     37.43mV    1.95V
4.785ns   1.8V       72.3mV     1.95V
5.8ns     1.8V       1.636V     1.95V
29.99ns   1.8V       1.65V      1.95V
[Falling Waveform]
| ALVCH16973_QOUT_18
R_fixture =   1k
C_fixture =   0
L_fixture =   0
V_fixture =   0
V_fixture_min = 0
V_fixture_max = 0
|   Time   V(typ)   V(min)   V(max)
0s        1.772V     1.608V     1.931V
2.335ns   1.772V     1.608V     1.948V
2.58ns    1.771V     1.608V     160.7mV
2.765ns   1.774V     1.608V     10.74mV
3.145ns   1.662V     1.608V     1.525mV
3.44ns    233mV      1.608V     494.6uV
3.71ns    10.21mV    1.607V     166.5uV
4.75ns    228uV      1.545V     2.689uV
5.785ns   7.898uV    14.47mV    139.2nV
29.99ns   4.363nV    13.3nV     1.568nV
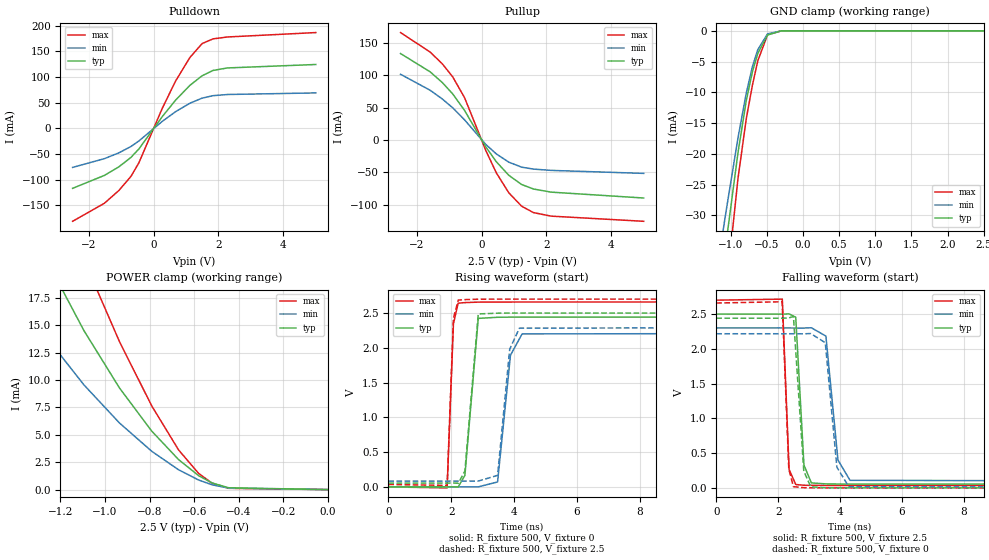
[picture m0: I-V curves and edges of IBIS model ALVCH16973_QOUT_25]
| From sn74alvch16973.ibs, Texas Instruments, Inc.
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[Model]   ALVCH16973_QOUT_25
Model_type  3-state
Enable   Active-Low
Vref =   0
Rref =   500
Cref =   30p
Vmeas =   1.25
| variable   typ   min   max
C_comp   2.87pF   2.65pF   3.16pF
| C_pullup   4.06pF   3.17pF   4.61pF
| C_pulldown   4.14pF   2.84pF   5.85pF
| C_tri-state   2.87pF   2.65pF   3.16pF
[Temperature Range]   40   100   -40
| Ambient temperature   25   85   -40
[Voltage range]   2.5   2.3   2.7
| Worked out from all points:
|   slope of the pulldown table from 0 to 0.375 V, typ, clamps not added: 11.7 ohm
|   slope of the pullup table from 0 to 0.375 V, typ, clamps not added: 13.2 ohm
|   GND clamp passes 1 mA (typ) near -0.51 V on its own axis
|   POWER clamp passes 1 mA (typ) near -0.56 V on its own axis
|   rising waveform, R_fixture 500, V_fixture 0: 20-80 % time 126ps typ, 231ps min, 83.5ps max; typ from 0 V to 2.44 V
|   falling waveform, R_fixture 500, V_fixture 2.5: 20-80 % time 139ps typ, 236ps min, 88.6ps max; typ from 2.5 V to 0.055 V
|   rising waveform, R_fixture 500, V_fixture 2.5: 20-80 % time 122ps typ, 219ps min, 81.1ps max; typ from 0.055 V to 2.5 V
|   falling waveform, R_fixture 500, V_fixture 0: 20-80 % time 136ps typ, 231ps min, 88ps max; typ from 2.44 V to 0 V
[GND Clamp]
| ALVCH16973_QOUT_25
|   Voltage   I(typ)   I(min)   I(max)
-2.5V     -189.9mA   -156.1mA   -234.2mA
-1.26V    -53.59mA   -44.73mA   -66.76mA
-1.165V   -44.15mA   -37.12mA   -54.75mA
-1.085V   -36.44mA   -30.9mA    -44.9mA
-1.065V   -34.55mA   -29.38mA   -42.48mA
-900mV    -19.84mA   -17.43mA   -24.05mA
-785mV    -11.35mA   -10.12mA   -14.29mA
-700mV    -6.655mA   -5.82mA    -8.829mA
-625mV    -3.664mA   -3.042mA   -4.849mA
-490mV    -676.5uA   -488.6uA   -627uA
-300mV    -6.618uA   -7.999uA   -1.799uA
2.5V      778.1pA    402.2nA    50.15pA
[POWER Clamp]
| ALVCH16973_QOUT_25
|   Voltage   I(typ)   I(min)   I(max)
-2.5V     88.04mA    62.35mA    109.1mA
-1.52V    32.36mA    21.74mA    44.61mA
-1.495V   31.18mA    20.91mA    43.11mA
-1.27V    21.26mA    14.1mA     30.19mA
-1.095V   14.53mA    9.569mA    21mA
-935mV    9.273mA    6.078mA    13.5mA
-790mV    5.332mA    3.492mA    7.626mA
-670mV    2.74mA     1.812mA    3.624mA
-580mV    1.272mA    875.9uA    1.476mA
-520mV    606.9uA    440.4uA    595.4uA
-445mV    166.5uA    133.9uA    117.4uA
-31.15fV  778.1pA    1.999nA    60.95pA
[Pulldown]
| ALVCH16973_QOUT_25
|   Voltage   I(typ)   I(min)   I(max)
-2.5V     -116.7mA   -75.94mA   -180.9mA
-1.52V    -91.51mA   -58.89mA   -145.8mA
-1.075V   -74.92mA   -47.63mA   -121mA
-700mV    -56.45mA   -35.17mA   -93.45mA
-455mV    -39.93mA   -24.42mA   -66.85mA
265mV     22.95mA    13.69mA    39.02mA
675mV     54.98mA    32.57mA    92.13mA
1.115V    83.7mA     48.99mA    137.9mA
1.495V    102.6mA    59.02mA    165.3mA
1.83V     112.9mA    63.78mA    174.4mA
2.275V    117.8mA    66.07mA    178.1mA
5V        124.5mA    69.16mA    186.7mA
[Pullup]
| ALVCH16973_QOUT_25
|   Voltage   I(typ)   I(min)   I(max)
-2.5V     134mA      101.9mA    166.5mA
-1.585V   105.6mA    77.05mA    136.2mA
-1.21V    89.01mA    63.51mA    118mA
-890mV    71.4mA     49.86mA    97.84mA
-525mV    45.85mA    31.23mA    65.64mA
135mV     -10.99mA   -7.123mA   -16.78mA
455mV     -33.71mA   -21.58mA   -50.91mA
840mV     -54.72mA   -34.35mA   -81.84mA
1.235V    -68.97mA   -42.11mA   -102.6mA
1.6V      -75.94mA   -45.08mA   -112.5mA
2.145V    -80.8mA    -47.11mA   -118mA
5V        -89.91mA   -51.75mA   -126mA
[Ramp]
| ALVCH16973_QOUT_25
| variable   typ   min   max
dV/dt_r   1.47/1.31E-10   1.35/2.47E-10   1.60/8.56E-11
dV/dt_f   1.49/1.48E-10   1.35/2.50E-10   1.61/9.35E-11
R_load = 500
[Rising Waveform]
| ALVCH16973_QOUT_25
R_fixture =   500
C_fixture =   0
L_fixture =   0
V_fixture =   0
V_fixture_min = 0
V_fixture_max = 0
|   Time   V(typ)   V(min)   V(max)
0s        6.47nV     29.37nV    168pV
1.87ns    -6.963uV   3.465uV    -13.55mV
2.07ns    688.6uV    -25.75uV   2.345V
2.22ns    -1.122mV   -44.23uV   2.642V
2.435ns   165.9mV    12.67uV    2.65V
2.86ns    2.423V     825.6uV    2.657V
3.475ns   2.439V     71.31mV    2.658V
3.885ns   2.441V     1.893V     2.658V
4.255ns   2.441V     2.2V       2.659V
29.99ns   2.441V     2.217V     2.659V
[Falling Waveform]
| ALVCH16973_QOUT_25
R_fixture =   500
C_fixture =   0
L_fixture =   0
V_fixture =   2.5
V_fixture_min = 2.3
V_fixture_max = 2.7
|   Time   V(typ)   V(min)   V(max)
0s        2.5V       2.3V       2.7V
2.135ns   2.499V     2.3V       2.715V
2.355ns   2.503V     2.3V       264.5mV
2.57ns    2.455V     2.299V     48.1mV
2.835ns   327.6mV    2.299V     37.63mV
3.075ns   71.33mV    2.303V     35.87mV
3.545ns   57.06mV    2.183V     35.01mV
3.935ns   55.42mV    400.2mV    34.9mV
4.325ns   55.05mV    108.3mV    34.87mV
29.99ns   54.93mV    83.57mV    34.87mV
[Rising Waveform]
| ALVCH16973_QOUT_25
R_fixture =   500
C_fixture =   0
L_fixture =   0
V_fixture =   2.5
V_fixture_min = 2.3
V_fixture_max = 2.7
|   Time   V(typ)   V(min)   V(max)
0s        54.93mV    83.57mV    34.87mV
1.87ns    54.93mV    83.57mV    21.94mV
2.07ns    55.54mV    83.55mV    2.426V
2.225ns   53.02mV    83.54mV    2.686V
2.435ns   229.9mV    83.61mV    2.693V
2.86ns    2.487V     84.17mV    2.699V
3.475ns   2.498V     166mV      2.7V
3.86ns    2.5V       1.98V      2.7V
4.17ns    2.5V       2.283V     2.7V
29.99ns   2.5V       2.3V       2.7V
[Falling Waveform]
| ALVCH16973_QOUT_25
R_fixture =   500
C_fixture =   0
L_fixture =   0
V_fixture =   0
V_fixture_min = 0
V_fixture_max = 0
|   Time   V(typ)   V(min)   V(max)
0s        2.441V     2.217V     2.659V
2.13ns    2.44V      2.217V     2.677V
2.345ns   2.444V     2.217V     268.8mV
2.495ns   2.466V     2.217V     17.52mV
2.83ns    240.8mV    2.216V     2.634mV
3.055ns   14.93mV    2.22V      996.9uV
3.525ns   1.771mV    2.088V     144.2uV
3.9ns     421.1uV    297.6mV    30.61uV
4.285ns   97.79uV    16.42mV    6.527uV
29.99ns   4.921nV    18.26nV    -2.505nV
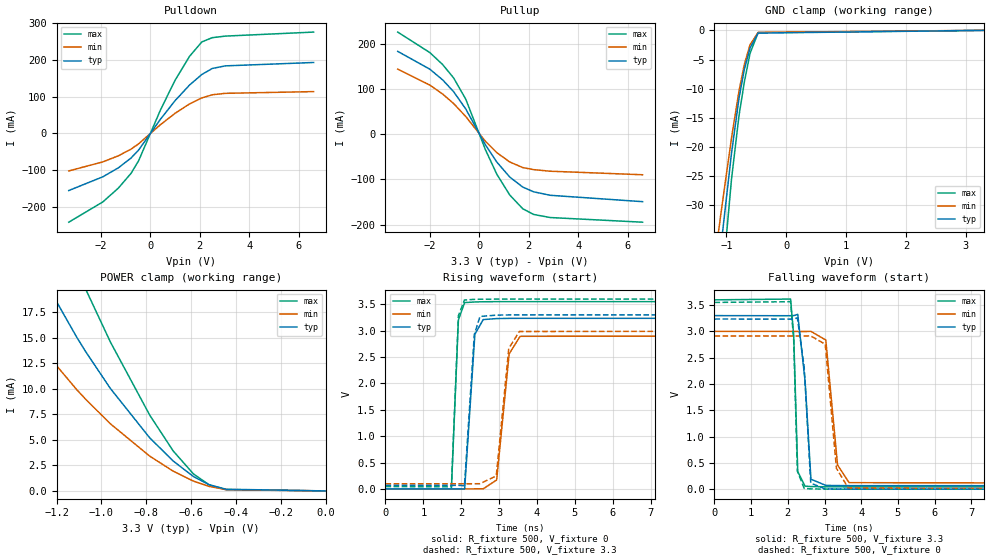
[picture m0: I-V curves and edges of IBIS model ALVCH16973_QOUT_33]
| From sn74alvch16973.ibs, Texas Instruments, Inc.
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[Model]   ALVCH16973_QOUT_33
Model_type  3-state
Enable   Active-Low
Vref =   0
Rref =   500
Cref =   50p
Vmeas =   1.5
| variable   typ   min   max
C_comp   2.79pF   2.56pF   3.13pF
| C_pullup   3.90pF   3.12pF   4.52pF
| C_pulldown   3.83pF   2.76pF   5.52pF
| C_tri-state   2.79pF   2.56pF   3.13pF
[Temperature Range]   40   100   -40
| Ambient temperature   25   85   -40
[Voltage range]   3.3   3   3.6
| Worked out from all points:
|   slope of the pulldown table from 0 to 0.495 V, typ, clamps not added: 10.7 ohm
|   slope of the pullup table from 0 to 0.495 V, typ, clamps not added: 10.9 ohm
|   GND clamp passes 1 mA (typ) near -0.51 V on its own axis
|   POWER clamp passes 1 mA (typ) near -0.56 V on its own axis
|   rising waveform, R_fixture 500, V_fixture 0: 20-80 % time 116ps typ, 195ps min, 75.4ps max; typ from 0 V to 3.23 V
|   falling waveform, R_fixture 500, V_fixture 3.3: 20-80 % time 110ps typ, 185ps min, 76.8ps max; typ from 3.3 V to 0.067 V
|   rising waveform, R_fixture 500, V_fixture 3.3: 20-80 % time 114ps typ, 189ps min, 74.5ps max; typ from 0.067 V to 3.3 V
|   falling waveform, R_fixture 500, V_fixture 0: 20-80 % time 108ps typ, 182ps min, 74.7ps max; typ from 3.23 V to 0 V
[GND Clamp]
| ALVCH16973_QOUT_33
|   Voltage   I(typ)   I(min)   I(max)
-3.3V     -283.4mA   -234mA     -345.6mA
-1.28V    -55.61mA   -46.35mA   -69.32mA
-1.25V    -52.59mA   -43.92mA   -65.49mA
-1.19V    -46.61mA   -39.1mA    -57.89mA
-1.16V    -43.67mA   -36.73mA   -54.13mA
-1.085V   -36.44mA   -30.9mA    -44.9mA
-915mV    -21.09mA   -18.46mA   -25.54mA
-790mV    -11.67mA   -10.41mA   -14.65mA
-700mV    -6.655mA   -5.82mA    -8.829mA
-605mV    -3.047mA   -2.459mA   -3.946mA
-470mV    -467.3uA   -343.4uA   -394uA
3.3V      1.064nA    5.58uA     89.37pA
[POWER Clamp]
| ALVCH16973_QOUT_33
|   Voltage   I(typ)   I(min)   I(max)
-3.3V     142.7mA    104.9mA    166.2mA
-1.5V     31.41mA    21.08mA    43.41mA
-1.275V   21.46mA    14.24mA    30.46mA
-1.11V    15.07mA    9.929mA    21.75mA
-1.07V    13.65mA    8.982mA    19.77mA
-960mV    10.04mA    6.581mA    14.6mA
-785mV    5.211mA    3.414mA    7.44mA
-680mV    2.93mA     1.935mA    3.914mA
-590mV    1.409mA    964.1uA    1.669mA
-520mV    606.9uA    440.4uA    595.4uA
-445mV    166.5uA    133.9uA    117.4uA
-48.03fV  1.064nA    2.227nA    114.6pA
[Pulldown]
| ALVCH16973_QOUT_33
|   Voltage   I(typ)   I(min)   I(max)
-3.3V     -155.3mA   -102mA     -241.3mA
-1.92V    -117.9mA   -77.39mA   -186.1mA
-1.295V   -93.6mA    -60.93mA   -148.7mA
-780mV    -66.83mA   -42.71mA   -108.4mA
-475mV    -45.21mA   -28.32mA   -74.34mA
405mV     38.2mA     23.55mA    63.12mA
995mV     88.61mA    54.39mA    143.9mA
1.585V    131.4mA    80.05mA    209.4mA
2.08V     160mA      96.3mA     248.5mA
2.505V    176.4mA    104.9mA    260.1mA
3.03V     183.4mA    108.8mA    264.3mA
6.6V      192.6mA    113.5mA    275.2mA
[Pullup]
| ALVCH16973_QOUT_33
|   Voltage   I(typ)   I(min)   I(max)
-3.3V     183mA      143.8mA    225.7mA
-2V       143.6mA    108.5mA    180.3mA
-1.48V    119.8mA    88.48mA    153.7mA
-1.04V    93.93mA    67.7mA     124.3mA
-550mV    55.76mA    39.02mA    77.44mA
245mV     -23.6mA    -15.83mA   -34.29mA
705mV     -61.65mA   -40.84mA   -88.44mA
1.23V     -94.91mA   -61.64mA   -134.7mA
1.755V    -117.1mA   -73.97mA   -165mA
2.19V     -127.5mA   -78.5mA    -177.6mA
2.865V    -135.3mA   -82.04mA   -184.5mA
6.6V      -149.4mA   -89.88mA   -194.8mA
[Ramp]
| ALVCH16973_QOUT_33
| variable   typ   min   max
dV/dt_r   1.96/1.21E-10   1.76/2.01E-10   2.14/7.74E-11
dV/dt_f   1.96/1.15E-10   1.76/1.92E-10   2.15/8.14E-11
R_load = 500
[Rising Waveform]
| ALVCH16973_QOUT_33
R_fixture =   500
C_fixture =   0
L_fixture =   0
V_fixture =   0
V_fixture_min = 0
V_fixture_max = 0
|   Time   V(typ)   V(min)   V(max)
0s        8.387nV    30.92nV    308.4pV
1.74ns    44.93uV    952.6nV    -5.241mV
1.925ns   681uV      -40.83uV   3.205V
2.09ns    -1.417mV   -49.34uV   3.533V
2.36ns    2.932V     682.1uV    3.545V
2.58ns    3.211V     1.417mV    3.549V
2.935ns   3.23V      168.6mV    3.551V
3.265ns   3.234V     2.561V     3.551V
3.555ns   3.235V     2.894V     3.551V
29.99ns   3.235V     2.913V     3.551V
[Falling Waveform]
| ALVCH16973_QOUT_33
R_fixture =   500
C_fixture =   0
L_fixture =   0
V_fixture =   3.3
V_fixture_min = 3
V_fixture_max = 3.6
|   Time   V(typ)   V(min)   V(max)
0s        3.3V       3V         3.6V
2.075ns   3.298V     3V         3.615V
2.16ns    3.301V     3V         2.926V
2.27ns    3.324V     2.999V     334.3mV
2.47ns    2.061V     2.998V     56.77mV
2.63ns    189mV      3.001V     49.84mV
3.035ns   72.11mV    2.836V     44.8mV
3.355ns   68.14mV    460.7mV    44.1mV
3.67ns    67.09mV    123.4mV    43.93mV
29.99ns   66.65mV    97.15mV    43.86mV
[Rising Waveform]
| ALVCH16973_QOUT_33
R_fixture =   500
C_fixture =   0
L_fixture =   0
V_fixture =   3.3
V_fixture_min = 3
V_fixture_max = 3.6
|   Time   V(typ)   V(min)   V(max)
0s        66.65mV    97.15mV    43.86mV
1.74ns    66.69mV    97.15mV    38.98mV
1.925ns   67.21mV    97.11mV    3.283V
2.085ns   59.05mV    97.11mV    3.582V
2.345ns   2.926V     97.71mV    3.594V
2.495ns   3.27V      98.22mV    3.597V
2.925ns   3.295V     247.1mV    3.599V
3.255ns   3.299V     2.665V     3.6V
3.535ns   3.3V       2.985V     3.6V
29.99ns   3.3V       3V         3.6V
[Falling Waveform]
| ALVCH16973_QOUT_33
R_fixture =   500
C_fixture =   0
L_fixture =   0
V_fixture =   0
V_fixture_min = 0
V_fixture_max = 0
|   Time   V(typ)   V(min)   V(max)
0s        3.235V     2.913V     3.551V
2.075ns   3.234V     2.913V     3.565V
2.16ns    3.237V     2.913V     2.842V
2.26ns    3.256V     2.912V     342.9mV
2.445ns   2.328V     2.912V     15.09mV
2.625ns   114.5mV    2.914V     5.753mV
3.02ns    4.671mV    2.756V     936.5uV
3.325ns   1.431mV    397.4mV    256.8uV
3.65ns    403uV      19.12mV    65.56uV
29.99ns   6.025nV    25.16nV    -591.8pV
